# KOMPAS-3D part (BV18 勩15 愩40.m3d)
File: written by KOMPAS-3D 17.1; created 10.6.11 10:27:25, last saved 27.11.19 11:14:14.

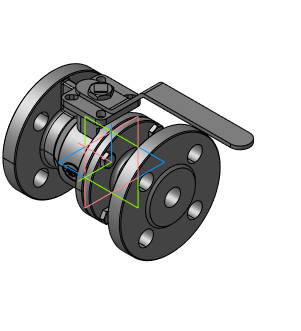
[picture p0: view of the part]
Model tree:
1. Плоскость XY
2. Плоскость ZX
3. Плоскость ZY
4. Ось X
5. Ось Y
6. Ось Z
7. Начало координат
8. Операция без истории:4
